UNITS
  DATABASE MICRONS 1000 ;
END UNITS


VERSION 5.7 ;
NAMESCASESENSITIVE ON ;
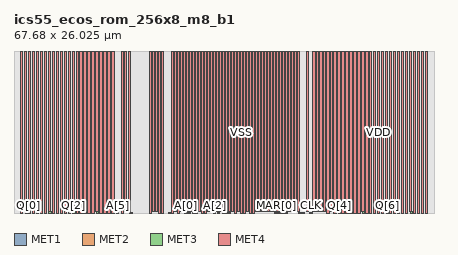
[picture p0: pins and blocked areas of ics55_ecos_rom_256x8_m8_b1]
MACRO ics55_ecos_rom_256x8_m8_b1
CLASS BLOCK ;
FOREIGN ics55_ecos_rom_256x8_m8_b1 0.000 0.000 ;
ORIGIN 0.000 0.000 ;
SIZE 67.680 BY 26.025 ;
SYMMETRY X Y R90 ;

PIN A[0]
  DIRECTION INPUT ;
  PORT
    LAYER MET1 ;
    RECT 27.510 0.000 27.890 0.140 ;
    LAYER MET2 ;
    RECT 27.510 0.000 27.890 0.140 ;
    LAYER MET3 ;
    RECT 27.510 0.000 27.890 0.140 ;
  END
  ANTENNADIFFAREA                0.46200         LAYER MET1 ;
  ANTENNADIFFAREA                0.46200         LAYER MET2 ;
  ANTENNADIFFAREA                0.46200         LAYER MET3 ;
  ANTENNAGATEAREA                0.06300         LAYER MET1 ;
  ANTENNAGATEAREA                0.06300         LAYER MET2 ;
  ANTENNAGATEAREA                0.06300         LAYER MET3 ;
  ANTENNAPARTIALMETALAREA        0.10115         LAYER MET1 ;
  ANTENNAPARTIALMETALAREA        0.13145         LAYER MET2 ;
  ANTENNAMAXAREACAR              0.88175         LAYER MET1 ;
  ANTENNAMAXAREACAR              3.81270         LAYER MET2 ;
  ANTENNAMAXAREACAR              4.65714         LAYER MET3 ;
END A[0]

PIN A[1]
  DIRECTION INPUT ;
  PORT
    LAYER MET1 ;
    RECT 28.140 0.000 28.520 0.140 ;
    LAYER MET2 ;
    RECT 28.140 0.000 28.520 0.140 ;
    LAYER MET3 ;
    RECT 28.140 0.000 28.520 0.140 ;
  END
  ANTENNADIFFAREA                0.46200         LAYER MET1 ;
  ANTENNADIFFAREA                0.46200         LAYER MET2 ;
  ANTENNADIFFAREA                0.46200         LAYER MET3 ;
  ANTENNAGATEAREA                0.06300         LAYER MET1 ;
  ANTENNAGATEAREA                0.06300         LAYER MET2 ;
  ANTENNAGATEAREA                0.06300         LAYER MET3 ;
  ANTENNAPARTIALMETALAREA        0.08795         LAYER MET1 ;
  ANTENNAPARTIALMETALAREA        0.11055         LAYER MET2 ;
  ANTENNAMAXAREACAR              0.67222         LAYER MET1 ;
  ANTENNAMAXAREACAR              3.27143         LAYER MET2 ;
  ANTENNAMAXAREACAR              4.11587         LAYER MET3 ;
END A[1]

PIN A[2]
  DIRECTION INPUT ;
  PORT
    LAYER MET1 ;
    RECT 32.165 0.000 32.545 0.140 ;
    LAYER MET2 ;
    RECT 32.165 0.000 32.545 0.140 ;
    LAYER MET3 ;
    RECT 32.165 0.000 32.545 0.140 ;
  END
  ANTENNADIFFAREA                0.45325         LAYER MET1 ;
  ANTENNADIFFAREA                0.45325         LAYER MET2 ;
  ANTENNADIFFAREA                0.45325         LAYER MET3 ;
  ANTENNAGATEAREA                0.06300         LAYER MET1 ;
  ANTENNAGATEAREA                0.06300         LAYER MET2 ;
  ANTENNAGATEAREA                0.06300         LAYER MET3 ;
  ANTENNAPARTIALMETALAREA        0.12345         LAYER MET1 ;
  ANTENNAPARTIALMETALAREA        0.13860         LAYER MET2 ;
  ANTENNAMAXAREACAR              1.23571         LAYER MET1 ;
  ANTENNAMAXAREACAR              4.28016         LAYER MET2 ;
  ANTENNAMAXAREACAR              5.12460         LAYER MET3 ;
END A[2]
PIN A[3]
  DIRECTION INPUT ;
  PORT
    LAYER MET1 ;
    RECT 34.570 0.000 34.950 0.140 ;
    LAYER MET2 ;
    RECT 34.570 0.000 34.950 0.140 ;
    LAYER MET3 ;
    RECT 34.570 0.000 34.950 0.140 ;
  END
  ANTENNADIFFAREA                0.45325         LAYER MET1 ;
  ANTENNADIFFAREA                0.45325         LAYER MET2 ;
  ANTENNADIFFAREA                0.45325         LAYER MET3 ;
  ANTENNAGATEAREA                0.06300         LAYER MET1 ;
  ANTENNAGATEAREA                0.06300         LAYER MET2 ;
  ANTENNAGATEAREA                0.06300         LAYER MET3 ;
  ANTENNAPARTIALMETALAREA        0.30500         LAYER MET1 ;
  ANTENNAPARTIALMETALAREA        1.15180         LAYER MET2 ;
  ANTENNAPARTIALMETALAREA        0.44285         LAYER MET3 ;
  ANTENNAMAXAREACAR              4.11746         LAYER MET1 ;
  ANTENNAMAXAREACAR              6.90238         LAYER MET2 ;
  ANTENNAMAXAREACAR              13.93175        LAYER MET3 ;
END A[3]
PIN A[4]
  DIRECTION INPUT ;
  PORT
    LAYER MET1 ;
    RECT 32.735 0.000 33.115 0.140 ;
    LAYER MET2 ;
    RECT 32.735 0.000 33.115 0.140 ;
    LAYER MET3 ;
    RECT 32.735 0.000 33.115 0.140 ;
  END
  ANTENNADIFFAREA                0.45325         LAYER MET1 ;
  ANTENNADIFFAREA                0.45325         LAYER MET2 ;
  ANTENNADIFFAREA                0.45325         LAYER MET3 ;
  ANTENNAGATEAREA                0.06300         LAYER MET1 ;
  ANTENNAGATEAREA                0.06300         LAYER MET2 ;
  ANTENNAGATEAREA                0.06300         LAYER MET3 ;
  ANTENNAPARTIALMETALAREA        0.11805         LAYER MET1 ;
  ANTENNAPARTIALMETALAREA        1.24320         LAYER MET2 ;
  ANTENNAMAXAREACAR              1.15000         LAYER MET1 ;
  ANTENNAMAXAREACAR              21.72778        LAYER MET2 ;
  ANTENNAMAXAREACAR              22.57222        LAYER MET3 ;
END A[4]
PIN A[5]
  DIRECTION INPUT ;
  PORT
    LAYER MET1 ;
    RECT 16.495 0.000 16.875 0.140 ;
    LAYER MET2 ;
    RECT 16.495 0.000 16.875 0.140 ;
    LAYER MET3 ;
    RECT 16.495 0.000 16.875 0.140 ;
  END
  ANTENNADIFFAREA                0.44100         LAYER MET1 ;
  ANTENNADIFFAREA                0.44100         LAYER MET2 ;
  ANTENNADIFFAREA                0.44100         LAYER MET3 ;
  ANTENNAGATEAREA                0.06300         LAYER MET1 ;
  ANTENNAGATEAREA                0.06300         LAYER MET2 ;
  ANTENNAGATEAREA                0.06300         LAYER MET3 ;
  ANTENNAPARTIALMETALAREA        0.28630         LAYER MET1 ;
  ANTENNAPARTIALMETALAREA        0.42040         LAYER MET2 ;
  ANTENNAMAXAREACAR              1.15397         LAYER MET1 ;
  ANTENNAMAXAREACAR              2.86508         LAYER MET2 ;
  ANTENNAMAXAREACAR              3.70952         LAYER MET3 ;
END A[5]
PIN A[6]
  DIRECTION INPUT ;
  PORT
    LAYER MET1 ;
    RECT 24.900 0.000 25.280 0.140 ;
    LAYER MET2 ;
    RECT 24.900 0.000 25.280 0.140 ;
    LAYER MET3 ;
    RECT 24.900 0.000 25.280 0.140 ;
  END
  ANTENNADIFFAREA                0.46080         LAYER MET1 ;
  ANTENNADIFFAREA                0.46080         LAYER MET2 ;
  ANTENNADIFFAREA                0.46080         LAYER MET3 ;
  ANTENNAGATEAREA                0.06300         LAYER MET1 ;
  ANTENNAGATEAREA                0.06300         LAYER MET2 ;
  ANTENNAGATEAREA                0.06300         LAYER MET3 ;
  ANTENNAPARTIALMETALAREA        0.15520         LAYER MET1 ;
  ANTENNAPARTIALMETALAREA        0.37960         LAYER MET2 ;
  ANTENNAPARTIALMETALAREA        0.70960         LAYER MET3 ;
  ANTENNAMAXAREACAR              1.60635         LAYER MET1 ;
  ANTENNAMAXAREACAR              2.77619         LAYER MET2 ;
  ANTENNAMAXAREACAR              14.03968        LAYER MET3 ;
END A[6]
PIN A[7]
  DIRECTION INPUT ;
  PORT
    LAYER MET1 ;
    RECT 18.680 0.000 19.060 0.140 ;
    LAYER MET2 ;
    RECT 18.680 0.000 19.060 0.140 ;
    LAYER MET3 ;
    RECT 18.680 0.000 19.060 0.140 ;
  END
  ANTENNADIFFAREA                0.45200         LAYER MET1 ;
  ANTENNADIFFAREA                0.45200         LAYER MET2 ;
  ANTENNADIFFAREA                0.45200         LAYER MET3 ;
  ANTENNAGATEAREA                0.06300         LAYER MET1 ;
  ANTENNAGATEAREA                0.06300         LAYER MET2 ;
  ANTENNAGATEAREA                0.06300         LAYER MET3 ;
  ANTENNAPARTIALMETALAREA        0.38420         LAYER MET1 ;
  ANTENNAPARTIALMETALAREA        0.87600         LAYER MET2 ;
  ANTENNAMAXAREACAR              6.09841         LAYER MET1 ;
  ANTENNAMAXAREACAR              20.84762        LAYER MET2 ;
  ANTENNAMAXAREACAR              21.69206        LAYER MET3 ;
END A[7]
PIN CEB
  DIRECTION INPUT ;
  PORT
    LAYER MET1 ;
    RECT 46.390 0.000 46.770 0.140 ;
    LAYER MET2 ;
    RECT 46.390 0.000 46.770 0.140 ;
    LAYER MET3 ;
    RECT 46.390 0.000 46.770 0.140 ;
  END
  ANTENNADIFFAREA                1.74525         LAYER MET1 ;
  ANTENNADIFFAREA                1.74525         LAYER MET2 ;
  ANTENNADIFFAREA                1.74525         LAYER MET3 ;
  ANTENNAGATEAREA                0.36600         LAYER MET1 ;
  ANTENNAGATEAREA                0.36600         LAYER MET2 ;
  ANTENNAGATEAREA                0.36600         LAYER MET3 ;
  ANTENNAPARTIALMETALAREA        0.34490         LAYER MET1 ;
  ANTENNAPARTIALMETALAREA        1.06035         LAYER MET2 ;
  ANTENNAPARTIALMETALAREA        1.03400         LAYER MET3 ;
  ANTENNAMAXAREACAR              1.95714         LAYER MET1 ;
  ANTENNAMAXAREACAR              17.35635        LAYER MET2 ;
  ANTENNAMAXAREACAR              34.61349        LAYER MET3 ;
END CEB
PIN CLK
  DIRECTION INPUT ;
  PORT
    LAYER MET1 ;
    RECT 47.645 0.000 48.025 0.140 ;
    LAYER MET2 ;
    RECT 47.645 0.000 48.025 0.140 ;
    LAYER MET3 ;
    RECT 47.645 0.000 48.025 0.140 ;
  END
  ANTENNADIFFAREA                1.49125         LAYER MET1 ;
  ANTENNADIFFAREA                1.49125         LAYER MET2 ;
  ANTENNADIFFAREA                1.49125         LAYER MET3 ;
  ANTENNAGATEAREA                0.30300         LAYER MET1 ;
  ANTENNAGATEAREA                0.30300         LAYER MET2 ;
  ANTENNAGATEAREA                0.30300         LAYER MET3 ;
  ANTENNAPARTIALMETALAREA        0.89645         LAYER MET1 ;
  ANTENNAPARTIALMETALAREA        0.34705         LAYER MET2 ;
  ANTENNAMAXAREACAR              11.55000        LAYER MET1 ;
  ANTENNAMAXAREACAR              17.05873        LAYER MET2 ;
  ANTENNAMAXAREACAR              17.90317        LAYER MET3 ;
END CLK
PIN MARE
  DIRECTION INPUT ;
  PORT
    LAYER MET1 ;
    RECT 45.830 0.000 46.210 0.140 ;
    LAYER MET2 ;
    RECT 45.830 0.000 46.210 0.140 ;
    LAYER MET3 ;
    RECT 45.830 0.000 46.210 0.140 ;
  END
  ANTENNADIFFAREA                0.45325         LAYER MET1 ;
  ANTENNADIFFAREA                0.45325         LAYER MET2 ;
  ANTENNADIFFAREA                0.45325         LAYER MET3 ;
  ANTENNAGATEAREA                0.06300         LAYER MET1 ;
  ANTENNAGATEAREA                0.06300         LAYER MET2 ;
  ANTENNAGATEAREA                0.06300         LAYER MET3 ;
  ANTENNAPARTIALMETALAREA        0.19300         LAYER MET1 ;
  ANTENNAPARTIALMETALAREA        0.28140         LAYER MET2 ;
  ANTENNAMAXAREACAR              2.33968         LAYER MET1 ;
  ANTENNAMAXAREACAR              7.65079         LAYER MET2 ;
  ANTENNAMAXAREACAR              8.49524         LAYER MET3 ;
END MARE
PIN MAR[0]
  DIRECTION INPUT ;
  PORT
    LAYER MET1 ;
    RECT 42.050 0.000 42.430 0.140 ;
    LAYER MET2 ;
    RECT 42.050 0.000 42.430 0.140 ;
    LAYER MET3 ;
    RECT 42.050 0.000 42.430 0.140 ;
  END
  ANTENNADIFFAREA                0.66850         LAYER MET1 ;
  ANTENNADIFFAREA                0.66850         LAYER MET2 ;
  ANTENNADIFFAREA                0.66850         LAYER MET3 ;
  ANTENNAGATEAREA                0.06300         LAYER MET1 ;
  ANTENNAGATEAREA                0.06300         LAYER MET2 ;
  ANTENNAGATEAREA                0.06300         LAYER MET3 ;
  ANTENNAPARTIALMETALAREA        0.09360         LAYER MET1 ;
  ANTENNAPARTIALMETALAREA        0.89580         LAYER MET2 ;
  ANTENNAMAXAREACAR              0.76190         LAYER MET1 ;
  ANTENNAMAXAREACAR              15.82540        LAYER MET2 ;
  ANTENNAMAXAREACAR              16.66984        LAYER MET3 ;
END MAR[0]
PIN MAR[1]
  DIRECTION INPUT ;
  PORT
    LAYER MET1 ;
    RECT 42.605 0.000 42.985 0.140 ;
    LAYER MET2 ;
    RECT 42.605 0.000 42.985 0.140 ;
    LAYER MET3 ;
    RECT 42.605 0.000 42.985 0.140 ;
  END
  ANTENNADIFFAREA                0.66850         LAYER MET1 ;
  ANTENNADIFFAREA                0.66850         LAYER MET2 ;
  ANTENNADIFFAREA                0.66850         LAYER MET3 ;
  ANTENNAGATEAREA                0.06300         LAYER MET1 ;
  ANTENNAGATEAREA                0.06300         LAYER MET2 ;
  ANTENNAGATEAREA                0.06300         LAYER MET3 ;
  ANTENNAPARTIALMETALAREA        0.09360         LAYER MET1 ;
  ANTENNAPARTIALMETALAREA        0.58560         LAYER MET2 ;
  ANTENNAMAXAREACAR              0.76190         LAYER MET1 ;
  ANTENNAMAXAREACAR              10.90159        LAYER MET2 ;
  ANTENNAMAXAREACAR              11.74603        LAYER MET3 ;
END MAR[1]
PIN MAR[2]
  DIRECTION INPUT ;
  PORT
    LAYER MET1 ;
    RECT 43.685 0.000 44.065 0.140 ;
    LAYER MET2 ;
    RECT 43.685 0.000 44.065 0.140 ;
    LAYER MET3 ;
    RECT 43.685 0.000 44.065 0.140 ;
  END
  ANTENNADIFFAREA                0.66850         LAYER MET1 ;
  ANTENNADIFFAREA                0.66850         LAYER MET2 ;
  ANTENNADIFFAREA                0.66850         LAYER MET3 ;
  ANTENNAGATEAREA                0.06300         LAYER MET1 ;
  ANTENNAGATEAREA                0.06300         LAYER MET2 ;
  ANTENNAGATEAREA                0.06300         LAYER MET3 ;
  ANTENNAPARTIALMETALAREA        0.09360         LAYER MET1 ;
  ANTENNAPARTIALMETALAREA        0.89400         LAYER MET2 ;
  ANTENNAMAXAREACAR              0.76190         LAYER MET1 ;
  ANTENNAMAXAREACAR              15.79683        LAYER MET2 ;
  ANTENNAMAXAREACAR              16.64127        LAYER MET3 ;
END MAR[2]
PIN MAR[3]
  DIRECTION INPUT ;
  PORT
    LAYER MET1 ;
    RECT 43.145 0.000 43.525 0.140 ;
    LAYER MET2 ;
    RECT 43.145 0.000 43.525 0.140 ;
    LAYER MET3 ;
    RECT 43.145 0.000 43.525 0.140 ;
  END
  ANTENNADIFFAREA                0.66850         LAYER MET1 ;
  ANTENNADIFFAREA                0.66850         LAYER MET2 ;
  ANTENNADIFFAREA                0.66850         LAYER MET3 ;
  ANTENNAGATEAREA                0.06300         LAYER MET1 ;
  ANTENNAGATEAREA                0.06300         LAYER MET2 ;
  ANTENNAGATEAREA                0.06300         LAYER MET3 ;
  ANTENNAPARTIALMETALAREA        0.09360         LAYER MET1 ;
  ANTENNAPARTIALMETALAREA        0.59100         LAYER MET2 ;
  ANTENNAMAXAREACAR              0.76190         LAYER MET1 ;
  ANTENNAMAXAREACAR              10.98730        LAYER MET2 ;
  ANTENNAMAXAREACAR              11.83175        LAYER MET3 ;
END MAR[3]
PIN Q[0]
  DIRECTION OUTPUT ;
  PORT
    LAYER MET1 ;
    RECT 1.795 0.000 2.155 0.180 ;
    LAYER MET2 ;
    RECT 1.795 0.000 2.155 0.180 ;
    LAYER MET3 ;
    RECT 1.795 0.000 2.155 0.180 ;
  END
  ANTENNADIFFAREA                0.48000         LAYER MET1 ;
  ANTENNADIFFAREA                0.48000         LAYER MET2 ;
  ANTENNADIFFAREA                0.48000         LAYER MET3 ;
  ANTENNAPARTIALMETALAREA        0.52500         LAYER MET1 ;
  ANTENNAPARTIALMETALAREA        0.25800         LAYER MET2 ;
END Q[0]
PIN Q[1]
  DIRECTION OUTPUT ;
  PORT
    LAYER MET1 ;
    RECT 5.635 0.000 5.995 0.180 ;
    LAYER MET2 ;
    RECT 5.635 0.000 5.995 0.180 ;
    LAYER MET3 ;
    RECT 5.635 0.000 5.995 0.180 ;
  END
  ANTENNADIFFAREA                0.48000         LAYER MET1 ;
  ANTENNADIFFAREA                0.48000         LAYER MET2 ;
  ANTENNADIFFAREA                0.48000         LAYER MET3 ;
  ANTENNAPARTIALMETALAREA        0.52500         LAYER MET1 ;
  ANTENNAPARTIALMETALAREA        0.25800         LAYER MET2 ;
END Q[1]
PIN Q[2]
  DIRECTION OUTPUT ;
  PORT
    LAYER MET1 ;
    RECT 9.475 0.000 9.835 0.180 ;
    LAYER MET2 ;
    RECT 9.475 0.000 9.835 0.180 ;
    LAYER MET3 ;
    RECT 9.475 0.000 9.835 0.180 ;
  END
  ANTENNADIFFAREA                0.48000         LAYER MET1 ;
  ANTENNADIFFAREA                0.48000         LAYER MET2 ;
  ANTENNADIFFAREA                0.48000         LAYER MET3 ;
  ANTENNAPARTIALMETALAREA        0.52500         LAYER MET1 ;
  ANTENNAPARTIALMETALAREA        0.25800         LAYER MET2 ;
END Q[2]
PIN Q[3]
  DIRECTION OUTPUT ;
  PORT
    LAYER MET1 ;
    RECT 13.315 0.000 13.675 0.180 ;
    LAYER MET2 ;
    RECT 13.315 0.000 13.675 0.180 ;
    LAYER MET3 ;
    RECT 13.315 0.000 13.675 0.180 ;
  END
  ANTENNADIFFAREA                0.48000         LAYER MET1 ;
  ANTENNADIFFAREA                0.48000         LAYER MET2 ;
  ANTENNADIFFAREA                0.48000         LAYER MET3 ;
  ANTENNAPARTIALMETALAREA        0.52500         LAYER MET1 ;
  ANTENNAPARTIALMETALAREA        0.25800         LAYER MET2 ;
END Q[3]
PIN Q[4]
  DIRECTION OUTPUT ;
  PORT
    LAYER MET1 ;
    RECT 52.325 0.000 52.685 0.180 ;
    LAYER MET2 ;
    RECT 52.325 0.000 52.685 0.180 ;
    LAYER MET3 ;
    RECT 52.325 0.000 52.685 0.180 ;
  END
  ANTENNADIFFAREA                0.48000         LAYER MET1 ;
  ANTENNADIFFAREA                0.48000         LAYER MET2 ;
  ANTENNADIFFAREA                0.48000         LAYER MET3 ;
  ANTENNAPARTIALMETALAREA        0.52500         LAYER MET1 ;
  ANTENNAPARTIALMETALAREA        0.25800         LAYER MET2 ;
END Q[4]
PIN Q[5]
  DIRECTION OUTPUT ;
  PORT
    LAYER MET1 ;
    RECT 56.165 0.000 56.525 0.180 ;
    LAYER MET2 ;
    RECT 56.165 0.000 56.525 0.180 ;
    LAYER MET3 ;
    RECT 56.165 0.000 56.525 0.180 ;
  END
  ANTENNADIFFAREA                0.48000         LAYER MET1 ;
  ANTENNADIFFAREA                0.48000         LAYER MET2 ;
  ANTENNADIFFAREA                0.48000         LAYER MET3 ;
  ANTENNAPARTIALMETALAREA        0.52500         LAYER MET1 ;
  ANTENNAPARTIALMETALAREA        0.25800         LAYER MET2 ;
END Q[5]
PIN Q[6]
  DIRECTION OUTPUT ;
  PORT
    LAYER MET1 ;
    RECT 60.005 0.000 60.365 0.180 ;
    LAYER MET2 ;
    RECT 60.005 0.000 60.365 0.180 ;
    LAYER MET3 ;
    RECT 60.005 0.000 60.365 0.180 ;
  END
  ANTENNADIFFAREA                0.48000         LAYER MET1 ;
  ANTENNADIFFAREA                0.48000         LAYER MET2 ;
  ANTENNADIFFAREA                0.48000         LAYER MET3 ;
  ANTENNAPARTIALMETALAREA        0.52500         LAYER MET1 ;
  ANTENNAPARTIALMETALAREA        0.25800         LAYER MET2 ;
END Q[6]
PIN Q[7]
  DIRECTION OUTPUT ;
  PORT
    LAYER MET1 ;
    RECT 63.845 0.000 64.205 0.180 ;
    LAYER MET2 ;
    RECT 63.845 0.000 64.205 0.180 ;
    LAYER MET3 ;
    RECT 63.845 0.000 64.205 0.180 ;
  END
  ANTENNADIFFAREA                0.48000         LAYER MET1 ;
  ANTENNADIFFAREA                0.48000         LAYER MET2 ;
  ANTENNADIFFAREA                0.48000         LAYER MET3 ;
  ANTENNAPARTIALMETALAREA        0.52500         LAYER MET1 ;
  ANTENNAPARTIALMETALAREA        0.25800         LAYER MET2 ;
END Q[7]
PIN VDD
  DIRECTION INOUT ;
  USE POWER ;
  PORT
    LAYER MET4 ;
    RECT 1.675 0.300 2.035 26.025 ;
    RECT 2.955 0.000 3.315 26.025 ;
    RECT 4.235 0.000 4.595 26.025 ;
    RECT 5.515 0.300 5.875 26.025 ;
    RECT 6.795 0.000 7.155 26.025 ;
    RECT 8.075 0.000 8.435 26.025 ;
    RECT 9.355 0.300 9.715 26.025 ;
    RECT 10.635 0.000 10.995 26.025 ;
    RECT 11.915 0.000 12.275 26.025 ;
    RECT 13.195 0.300 13.555 26.025 ;
    RECT 14.475 0.000 14.835 26.025 ;
    RECT 15.755 0.000 16.115 26.025 ;
    RECT 17.260 0.000 17.620 26.025 ;
    RECT 18.440 0.300 18.800 26.025 ;
    RECT 21.845 0.000 22.205 26.025 ;
    RECT 22.325 0.300 22.685 26.025 ;
    RECT 23.285 0.000 23.645 26.025 ;
    RECT 23.765 0.000 24.125 26.025 ;
    RECT 25.400 0.000 25.760 26.025 ;
    RECT 25.880 0.300 26.240 26.025 ;
    RECT 26.840 0.300 27.200 26.025 ;
    RECT 27.320 0.300 27.680 26.025 ;
    RECT 28.280 0.300 28.640 26.025 ;
    RECT 28.760 0.000 29.120 26.025 ;
    RECT 29.720 0.300 30.080 26.025 ;
    RECT 30.200 0.000 30.560 26.025 ;
    RECT 31.160 0.300 31.520 26.025 ;
    RECT 32.130 0.300 32.490 26.025 ;
    RECT 33.100 0.300 33.460 26.025 ;
    RECT 33.580 0.000 33.940 26.025 ;
    RECT 34.550 0.300 34.910 26.025 ;
    RECT 35.030 0.300 35.390 26.025 ;
    RECT 35.520 0.000 35.880 26.025 ;
    RECT 36.000 0.300 36.360 26.025 ;
    RECT 36.970 0.000 37.330 26.025 ;
    RECT 37.450 0.300 37.810 26.025 ;
    RECT 38.420 0.000 38.780 26.025 ;
    RECT 38.900 0.300 39.260 26.025 ;
    RECT 39.870 0.300 40.230 26.025 ;
    RECT 40.840 0.300 41.200 26.025 ;
    RECT 41.320 0.300 41.680 26.025 ;
    RECT 42.280 0.300 42.640 26.025 ;
    RECT 42.760 0.300 43.120 26.025 ;
    RECT 43.720 0.300 44.080 26.025 ;
    RECT 44.200 0.300 44.560 26.025 ;
    RECT 45.160 0.300 45.520 26.025 ;
    RECT 45.640 0.300 46.000 26.025 ;
    RECT 47.135 0.300 47.495 26.025 ;
    RECT 49.300 0.300 49.660 26.025 ;
    RECT 50.400 0.000 50.760 26.025 ;
    RECT 52.205 0.300 52.565 26.025 ;
    RECT 53.485 0.000 53.845 26.025 ;
    RECT 54.765 0.000 55.125 26.025 ;
    RECT 56.045 0.300 56.405 26.025 ;
    RECT 57.325 0.000 57.685 26.025 ;
    RECT 58.605 0.000 58.965 26.025 ;
    RECT 59.885 0.300 60.245 26.025 ;
    RECT 61.165 0.000 61.525 26.025 ;
    RECT 62.445 0.000 62.805 26.025 ;
    RECT 63.725 0.300 64.085 26.025 ;
    RECT 65.005 0.000 65.365 26.025 ;
    RECT 66.285 0.000 66.645 26.025 ;
  END
END VDD
PIN VSS
  DIRECTION INOUT ;
  USE GROUND ;
  PORT
    LAYER MET4 ;
    RECT 1.035 0.000 1.395 26.025 ;
    RECT 2.315 0.000 2.675 26.025 ;
    RECT 3.595 0.000 3.955 26.025 ;
    RECT 4.875 0.000 5.235 26.025 ;
    RECT 6.155 0.000 6.515 26.025 ;
    RECT 7.435 0.000 7.795 26.025 ;
    RECT 8.715 0.000 9.075 26.025 ;
    RECT 9.995 0.000 10.355 26.025 ;
    RECT 11.275 0.000 11.635 26.025 ;
    RECT 12.555 0.000 12.915 26.025 ;
    RECT 13.835 0.000 14.195 26.025 ;
    RECT 15.115 0.000 15.475 26.025 ;
    RECT 17.840 0.300 18.200 26.025 ;
    RECT 22.805 0.300 23.165 26.025 ;
    RECT 26.360 0.000 26.720 26.025 ;
    RECT 27.800 0.300 28.160 26.025 ;
    RECT 29.240 0.000 29.600 26.025 ;
    RECT 30.680 0.000 31.040 26.025 ;
    RECT 31.645 0.300 32.005 26.025 ;
    RECT 32.620 0.300 32.980 26.025 ;
    RECT 34.070 0.000 34.430 26.025 ;
    RECT 36.480 0.000 36.840 26.025 ;
    RECT 37.930 0.000 38.290 26.025 ;
    RECT 39.380 0.300 39.740 26.025 ;
    RECT 40.360 0.300 40.720 26.025 ;
    RECT 41.800 0.300 42.160 26.025 ;
    RECT 43.240 0.300 43.600 26.025 ;
    RECT 44.680 0.300 45.040 26.025 ;
    RECT 48.160 0.300 48.520 26.025 ;
    RECT 48.750 0.300 49.110 26.025 ;
    RECT 49.850 0.300 50.210 26.025 ;
    RECT 50.950 0.300 51.310 26.025 ;
    RECT 51.565 0.000 51.925 26.025 ;
    RECT 52.845 0.000 53.205 26.025 ;
    RECT 54.125 0.000 54.485 26.025 ;
    RECT 55.405 0.000 55.765 26.025 ;
    RECT 56.685 0.000 57.045 26.025 ;
    RECT 57.965 0.000 58.325 26.025 ;
    RECT 59.245 0.000 59.605 26.025 ;
    RECT 60.525 0.000 60.885 26.025 ;
    RECT 61.805 0.000 62.165 26.025 ;
    RECT 63.085 0.000 63.445 26.025 ;
    RECT 64.365 0.000 64.725 26.025 ;
    RECT 65.645 0.000 66.005 26.025 ;
  END
END VSS
OBS
  LAYER MET1 SPACING 0.090 ;
    POLYGON 67.680 0.000 67.680 26.025 
            0.000 26.025 0.000 0.000 
            1.795 0.000 1.795 0.180 
            2.155 0.180 2.155 0.000 
            5.635 0.000 5.635 0.180 
            5.995 0.180 5.995 0.000 
            9.475 0.000 9.475 0.180 
            9.835 0.180 9.835 0.000 
            13.315 0.000 13.315 0.180 
            13.675 0.180 13.675 0.000 
            16.495 0.000 16.495 0.140 
            16.875 0.140 16.875 0.000 
            18.680 0.000 18.680 0.140 
            19.060 0.140 19.060 0.000 
            24.900 0.000 24.900 0.140 
            25.280 0.140 25.280 0.000 
            27.510 0.000 27.510 0.140 
            27.890 0.140 27.890 0.000 
            28.140 0.000 28.140 0.140 
            28.520 0.140 28.520 0.000 
            32.165 0.000 32.165 0.140 
            32.545 0.140 32.545 0.000 
            32.735 0.000 32.735 0.140 
            33.115 0.140 33.115 0.000 
            34.570 0.000 34.570 0.140 
            34.950 0.140 34.950 0.000 
            42.050 0.000 42.050 0.140 
            42.430 0.140 42.430 0.000 
            42.605 0.000 42.605 0.140 
            42.985 0.140 42.985 0.000 
            43.145 0.000 43.145 0.140 
            43.525 0.140 43.525 0.000 
            43.685 0.000 43.685 0.140 
            44.065 0.140 44.065 0.000 
            45.830 0.000 45.830 0.140 
            46.210 0.140 46.210 0.000 
            46.390 0.000 46.390 0.140 
            46.770 0.140 46.770 0.000 
            47.645 0.000 47.645 0.140 
            48.025 0.140 48.025 0.000 
            52.325 0.000 52.325 0.180 
            52.685 0.180 52.685 0.000 
            56.165 0.000 56.165 0.180 
            56.525 0.180 56.525 0.000 
            60.005 0.000 60.005 0.180 
            60.365 0.180 60.365 0.000 
            63.845 0.000 63.845 0.180 
            64.205 0.180 64.205 0.000 
            67.680 0.000 ;
  LAYER VIA1 SPACING 0.110 ;
    RECT 0.000 0.000 67.680 26.025 ;
  LAYER MET2 SPACING 0.100 ;
    POLYGON 67.680 0.000 67.680 26.025 
            0.000 26.025 0.000 0.000 
            1.795 0.000 1.795 0.180 
            2.155 0.180 2.155 0.000 
            5.635 0.000 5.635 0.180 
            5.995 0.180 5.995 0.000 
            9.475 0.000 9.475 0.180 
            9.835 0.180 9.835 0.000 
            13.315 0.000 13.315 0.180 
            13.675 0.180 13.675 0.000 
            16.495 0.000 16.495 0.140 
            16.875 0.140 16.875 0.000 
            18.680 0.000 18.680 0.140 
            19.060 0.140 19.060 0.000 
            24.900 0.000 24.900 0.140 
            25.280 0.140 25.280 0.000 
            27.510 0.000 27.510 0.140 
            27.890 0.140 27.890 0.000 
            28.140 0.000 28.140 0.140 
            28.520 0.140 28.520 0.000 
            32.165 0.000 32.165 0.140 
            32.545 0.140 32.545 0.000 
            32.735 0.000 32.735 0.140 
            33.115 0.140 33.115 0.000 
            34.570 0.000 34.570 0.140 
            34.950 0.140 34.950 0.000 
            42.050 0.000 42.050 0.140 
            42.430 0.140 42.430 0.000 
            42.605 0.000 42.605 0.140 
            42.985 0.140 42.985 0.000 
            43.145 0.000 43.145 0.140 
            43.525 0.140 43.525 0.000 
            43.685 0.000 43.685 0.140 
            44.065 0.140 44.065 0.000 
            45.830 0.000 45.830 0.140 
            46.210 0.140 46.210 0.000 
            46.390 0.000 46.390 0.140 
            46.770 0.140 46.770 0.000 
            47.645 0.000 47.645 0.140 
            48.025 0.140 48.025 0.000 
            52.325 0.000 52.325 0.180 
            52.685 0.180 52.685 0.000 
            56.165 0.000 56.165 0.180 
            56.525 0.180 56.525 0.000 
            60.005 0.000 60.005 0.180 
            60.365 0.180 60.365 0.000 
            63.845 0.000 63.845 0.180 
            64.205 0.180 64.205 0.000 
            67.680 0.000 ;
  LAYER VIA2 SPACING 0.110 ;
    RECT 0.000 0.000 67.680 26.025 ;
  LAYER MET3 SPACING 0.150 ;
    POLYGON 67.680 0.000 67.680 26.025 
            0.000 26.025 0.000 0.000 
            1.795 0.000 1.795 0.180 
            2.155 0.180 2.155 0.000 
            5.635 0.000 5.635 0.180 
            5.995 0.180 5.995 0.000 
            9.475 0.000 9.475 0.180 
            9.835 0.180 9.835 0.000 
            13.315 0.000 13.315 0.180 
            13.675 0.180 13.675 0.000 
            16.495 0.000 16.495 0.140 
            16.875 0.140 16.875 0.000 
            18.680 0.000 18.680 0.140 
            19.060 0.140 19.060 0.000 
            24.900 0.000 24.900 0.140 
            25.280 0.140 25.280 0.000 
            27.510 0.000 27.510 0.140 
            27.890 0.140 27.890 0.000 
            28.140 0.000 28.140 0.140 
            28.520 0.140 28.520 0.000 
            32.165 0.000 32.165 0.140 
            32.545 0.140 32.545 0.000 
            32.735 0.000 32.735 0.140 
            33.115 0.140 33.115 0.000 
            34.570 0.000 34.570 0.140 
            34.950 0.140 34.950 0.000 
            42.050 0.000 42.050 0.140 
            42.430 0.140 42.430 0.000 
            42.605 0.000 42.605 0.140 
            42.985 0.140 42.985 0.000 
            43.145 0.000 43.145 0.140 
            43.525 0.140 43.525 0.000 
            43.685 0.000 43.685 0.140 
            44.065 0.140 44.065 0.000 
            45.830 0.000 45.830 0.140 
            46.210 0.140 46.210 0.000 
            46.390 0.000 46.390 0.140 
            46.770 0.140 46.770 0.000 
            47.645 0.000 47.645 0.140 
            48.025 0.140 48.025 0.000 
            52.325 0.000 52.325 0.180 
            52.685 0.180 52.685 0.000 
            56.165 0.000 56.165 0.180 
            56.525 0.180 56.525 0.000 
            60.005 0.000 60.005 0.180 
            60.365 0.180 60.365 0.000 
            63.845 0.000 63.845 0.180 
            64.205 0.180 64.205 0.000 
            67.680 0.000 ;
  LAYER VIA3 SPACING 0.110 ;
    RECT 0.000 0.000 67.680 26.025 ;
  LAYER MET4 SPACING 0.150 ;
    RECT 0.000 0.000 1.035 26.025 ;
    POLYGON 2.315 0.000 2.315 26.025 
            2.035 26.025 2.035 0.300 
            1.675 0.300 1.675 26.025 
            1.395 26.025 1.395 0.000 
            2.315 0.000 ;
    RECT 2.675 0.000 2.955 26.025 ;
    RECT 3.315 0.000 3.595 26.025 ;
    RECT 3.955 0.000 4.235 26.025 ;
    RECT 4.595 0.000 4.875 26.025 ;
    POLYGON 6.155 0.000 6.155 26.025 
            5.875 26.025 5.875 0.300 
            5.515 0.300 5.515 26.025 
            5.235 26.025 5.235 0.000 
            6.155 0.000 ;
    RECT 6.515 0.000 6.795 26.025 ;
    RECT 7.155 0.000 7.435 26.025 ;
    RECT 7.795 0.000 8.075 26.025 ;
    RECT 8.435 0.000 8.715 26.025 ;
    POLYGON 9.995 0.000 9.995 26.025 
            9.715 26.025 9.715 0.300 
            9.355 0.300 9.355 26.025 
            9.075 26.025 9.075 0.000 
            9.995 0.000 ;
    RECT 10.355 0.000 10.635 26.025 ;
    RECT 10.995 0.000 11.275 26.025 ;
    RECT 11.635 0.000 11.915 26.025 ;
    RECT 12.275 0.000 12.555 26.025 ;
    POLYGON 13.835 0.000 13.835 26.025 
            13.555 26.025 13.555 0.300 
            13.195 0.300 13.195 26.025 
            12.915 26.025 12.915 0.000 
            13.835 0.000 ;
    RECT 14.195 0.000 14.475 26.025 ;
    RECT 14.835 0.000 15.115 26.025 ;
    RECT 15.475 0.000 15.755 26.025 ;
    RECT 16.115 0.000 17.260 26.025 ;
    POLYGON 21.845 0.000 21.845 26.025 
            18.800 26.025 18.800 0.300 
            18.440 0.300 18.440 26.025 
            18.200 26.025 18.200 0.300 
            17.840 0.300 17.840 26.025 
            17.620 26.025 17.620 0.000 
            21.845 0.000 ;
    POLYGON 23.285 0.000 23.285 26.025 
            23.165 26.025 23.165 0.300 
            22.805 0.300 22.805 26.025 
            22.685 26.025 22.685 0.300 
            22.325 0.300 22.325 26.025 
            22.205 26.025 22.205 0.000 
            23.285 0.000 ;
    RECT 23.645 0.000 23.765 26.025 ;
    RECT 24.125 0.000 25.400 26.025 ;
    POLYGON 26.360 0.000 26.360 26.025 
            26.240 26.025 26.240 0.300 
            25.880 0.300 25.880 26.025 
            25.760 26.025 25.760 0.000 
            26.360 0.000 ;
    POLYGON 28.760 0.000 28.760 26.025 
            28.640 26.025 28.640 0.300 
            28.280 0.300 28.280 26.025 
            28.160 26.025 28.160 0.300 
            27.800 0.300 27.800 26.025 
            27.680 26.025 27.680 0.300 
            27.320 0.300 27.320 26.025 
            27.200 26.025 27.200 0.300 
            26.840 0.300 26.840 26.025 
            26.720 26.025 26.720 0.000 
            28.760 0.000 ;
    RECT 29.120 0.000 29.240 26.025 ;
    POLYGON 30.200 0.000 30.200 26.025 
            30.080 26.025 30.080 0.300 
            29.720 0.300 29.720 26.025 
            29.600 26.025 29.600 0.000 
            30.200 0.000 ;
    RECT 30.560 0.000 30.680 26.025 ;
    POLYGON 33.580 0.000 33.580 26.025 
            33.460 26.025 33.460 0.300 
            33.100 0.300 33.100 26.025 
            32.980 26.025 32.980 0.300 
            32.620 0.300 32.620 26.025 
            32.490 26.025 32.490 0.300 
            32.130 0.300 32.130 26.025 
            32.005 26.025 32.005 0.300 
            31.645 0.300 31.645 26.025 
            31.520 26.025 31.520 0.300 
            31.160 0.300 31.160 26.025 
            31.040 26.025 31.040 0.000 
            33.580 0.000 ;
    RECT 33.940 0.000 34.070 26.025 ;
    POLYGON 35.520 0.000 35.520 26.025 
            35.390 26.025 35.390 0.300 
            35.030 0.300 35.030 26.025 
            34.910 26.025 34.910 0.300 
            34.550 0.300 34.550 26.025 
            34.430 26.025 34.430 0.000 
            35.520 0.000 ;
    POLYGON 36.480 0.000 36.480 26.025 
            36.360 26.025 36.360 0.300 
            36.000 0.300 36.000 26.025 
            35.880 26.025 35.880 0.000 
            36.480 0.000 ;
    RECT 36.840 0.000 36.970 26.025 ;
    POLYGON 37.930 0.000 37.930 26.025 
            37.810 26.025 37.810 0.300 
            37.450 0.300 37.450 26.025 
            37.330 26.025 37.330 0.000 
            37.930 0.000 ;
    RECT 38.290 0.000 38.420 26.025 ;
    POLYGON 50.400 0.000 50.400 26.025 
            50.210 26.025 50.210 0.300 
            49.850 0.300 49.850 26.025 
            49.660 26.025 49.660 0.300 
            49.300 0.300 49.300 26.025 
            49.110 26.025 49.110 0.300 
            48.750 0.300 48.750 26.025 
            48.520 26.025 48.520 0.300 
            48.160 0.300 48.160 26.025 
            47.495 26.025 47.495 0.300 
            47.135 0.300 47.135 26.025 
            46.000 26.025 46.000 0.300 
            45.640 0.300 45.640 26.025 
            45.520 26.025 45.520 0.300 
            45.160 0.300 45.160 26.025 
            45.040 26.025 45.040 0.300 
            44.680 0.300 44.680 26.025 
            44.560 26.025 44.560 0.300 
            44.200 0.300 44.200 26.025 
            44.080 26.025 44.080 0.300 
            43.720 0.300 43.720 26.025 
            43.600 26.025 43.600 0.300 
            43.240 0.300 43.240 26.025 
            43.120 26.025 43.120 0.300 
            42.760 0.300 42.760 26.025 
            42.640 26.025 42.640 0.300 
            42.280 0.300 42.280 26.025 
            42.160 26.025 42.160 0.300 
            41.800 0.300 41.800 26.025 
            41.680 26.025 41.680 0.300 
            41.320 0.300 41.320 26.025 
            41.200 26.025 41.200 0.300 
            40.840 0.300 40.840 26.025 
            40.720 26.025 40.720 0.300 
            40.360 0.300 40.360 26.025 
            40.230 26.025 40.230 0.300 
            39.870 0.300 39.870 26.025 
            39.740 26.025 39.740 0.300 
            39.380 0.300 39.380 26.025 
            39.260 26.025 39.260 0.300 
            38.900 0.300 38.900 26.025 
            38.780 26.025 38.780 0.000 
            50.400 0.000 ;
    POLYGON 51.565 0.000 51.565 26.025 
            51.310 26.025 51.310 0.300 
            50.950 0.300 50.950 26.025 
            50.760 26.025 50.760 0.000 
            51.565 0.000 ;
    POLYGON 52.845 0.000 52.845 26.025 
            52.565 26.025 52.565 0.300 
            52.205 0.300 52.205 26.025 
            51.925 26.025 51.925 0.000 
            52.845 0.000 ;
    RECT 53.205 0.000 53.485 26.025 ;
    RECT 53.845 0.000 54.125 26.025 ;
    RECT 54.485 0.000 54.765 26.025 ;
    RECT 55.125 0.000 55.405 26.025 ;
    POLYGON 56.685 0.000 56.685 26.025 
            56.405 26.025 56.405 0.300 
            56.045 0.300 56.045 26.025 
            55.765 26.025 55.765 0.000 
            56.685 0.000 ;
    RECT 57.045 0.000 57.325 26.025 ;
    RECT 57.685 0.000 57.965 26.025 ;
    RECT 58.325 0.000 58.605 26.025 ;
    RECT 58.965 0.000 59.245 26.025 ;
    POLYGON 60.525 0.000 60.525 26.025 
            60.245 26.025 60.245 0.300 
            59.885 0.300 59.885 26.025 
            59.605 26.025 59.605 0.000 
            60.525 0.000 ;
    RECT 60.885 0.000 61.165 26.025 ;
    RECT 61.525 0.000 61.805 26.025 ;
    RECT 62.165 0.000 62.445 26.025 ;
    RECT 62.805 0.000 63.085 26.025 ;
    POLYGON 64.365 0.000 64.365 26.025 
            64.085 26.025 64.085 0.300 
            63.725 0.300 63.725 26.025 
            63.445 26.025 63.445 0.000 
            64.365 0.000 ;
    RECT 64.725 0.000 65.005 26.025 ;
    RECT 65.365 0.000 65.645 26.025 ;
    RECT 66.005 0.000 66.285 26.025 ;
    RECT 66.645 0.000 67.680 26.025 ;
END
END ics55_ecos_rom_256x8_m8_b1
END LIBRARY

